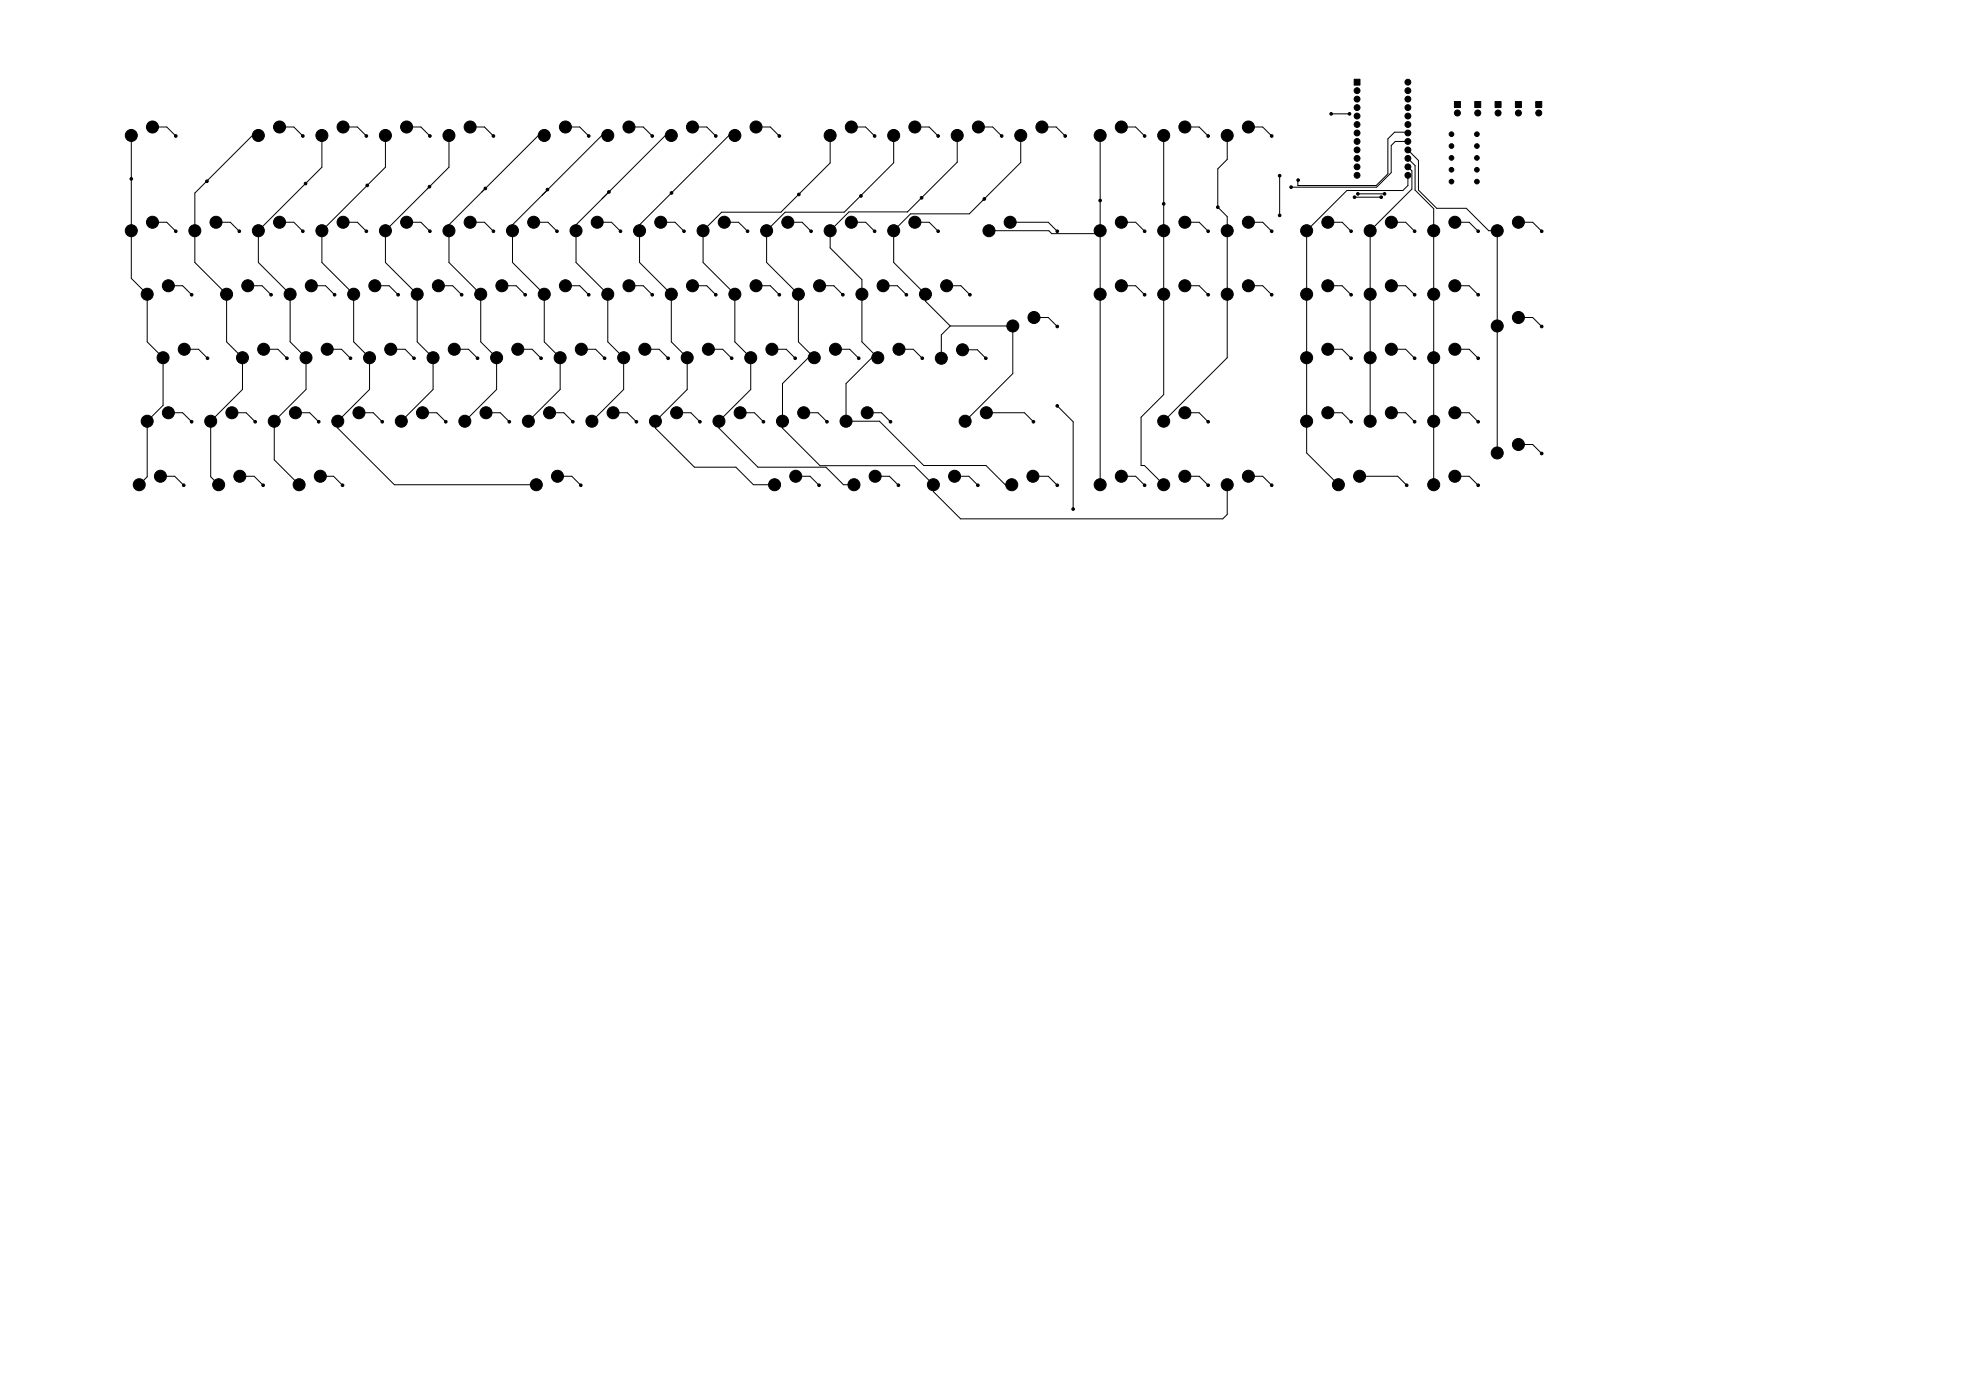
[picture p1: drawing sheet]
<svg xmlns="http://www.w3.org/2000/svg" width="594mm" height="420mm" viewBox="0 0 594 420" stroke-linecap="round" stroke-linejoin="round" font-family="sans-serif">
<g fill="#000" stroke="#000" stroke-width=".3">
<path d="M406 23.8h1.8v1.7h-1.8zM436.1 30.5h1.8v1.8h-1.8zM442.2 30.5h1.8v1.8h-1.8zM448.3 30.5h1.8v1.8h-1.8zM454.4 30.5h1.8v1.8h-1.8zM460.5 30.5h1.8v1.8h-1.8z"/>
<circle cx="45.7" cy="38.1" r="1.8"/>
<circle cx="83.8" cy="38.1" r="1.8"/>
<circle cx="102.9" cy="38.1" r="1.8"/>
<circle cx="121.9" cy="38.1" r="1.8"/>
<circle cx="141" cy="38.1" r="1.8"/>
<circle cx="169.5" cy="38.1" r="1.8"/>
<circle cx="188.6" cy="38.1" r="1.8"/>
<circle cx="207.6" cy="38.1" r="1.8"/>
<circle cx="226.7" cy="38.1" r="1.8"/>
<circle cx="255.3" cy="38.1" r="1.8"/>
<circle cx="274.3" cy="38.1" r="1.8"/>
<circle cx="293.4" cy="38.1" r="1.8"/>
<circle cx="312.4" cy="38.1" r="1.8"/>
<circle cx="336.2" cy="38.1" r="1.8"/>
<circle cx="355.3" cy="38.1" r="1.8"/>
<circle cx="374.3" cy="38.1" r="1.8"/>
<circle cx="399.2" cy="34.2" r=".4"/>
<circle cx="404.7" cy="34.2" r=".4"/>
<circle cx="406.9" cy="39.9" r=".88"/>
<circle cx="406.9" cy="34.8" r=".88"/>
<circle cx="406.9" cy="27.2" r=".88"/>
<circle cx="406.9" cy="29.7" r=".88"/>
<circle cx="406.9" cy="32.3" r=".88"/>
<circle cx="406.9" cy="37.4" r=".88"/>
<circle cx="422.2" cy="32.3" r=".88"/>
<circle cx="422.2" cy="27.2" r=".88"/>
<circle cx="422.2" cy="39.9" r=".88"/>
<circle cx="422.2" cy="37.4" r=".88"/>
<circle cx="422.2" cy="24.7" r=".88"/>
<circle cx="422.2" cy="34.8" r=".88"/>
<circle cx="422.2" cy="29.7" r=".88"/>
<circle cx="437" cy="33.9" r=".9"/>
<circle cx="443.1" cy="33.9" r=".9"/>
<circle cx="449.2" cy="33.9" r=".9"/>
<circle cx="455.3" cy="33.9" r=".9"/>
<circle cx="461.4" cy="33.9" r=".9"/>
<circle cx="39.4" cy="53.7" r=".4"/>
<circle cx="39.4" cy="40.6" r="1.8"/>
<circle cx="52.7" cy="40.8" r=".4"/>
<circle cx="62.1" cy="54.4" r=".4"/>
<circle cx="77.5" cy="40.6" r="1.8"/>
<circle cx="90.8" cy="40.8" r=".4"/>
<circle cx="91.6" cy="55.1" r=".4"/>
<circle cx="96.5" cy="40.6" r="1.8"/>
<circle cx="109.9" cy="40.8" r=".4"/>
<circle cx="110.1" cy="55.6" r=".4"/>
<circle cx="115.6" cy="40.6" r="1.8"/>
<circle cx="128.8" cy="56" r=".4"/>
<circle cx="128.9" cy="40.8" r=".4"/>
<circle cx="134.6" cy="40.6" r="1.8"/>
<circle cx="145.5" cy="56.5" r=".4"/>
<circle cx="148" cy="40.8" r=".4"/>
<circle cx="163.2" cy="40.6" r="1.8"/>
<circle cx="164.2" cy="56.9" r=".4"/>
<circle cx="176.5" cy="40.8" r=".4"/>
<circle cx="182.2" cy="40.6" r="1.8"/>
<circle cx="182.6" cy="57.6" r=".4"/>
<circle cx="195.6" cy="40.8" r=".4"/>
<circle cx="201.3" cy="40.6" r="1.8"/>
<circle cx="201.4" cy="57.9" r=".4"/>
<circle cx="214.6" cy="40.8" r=".4"/>
<circle cx="220.3" cy="40.6" r="1.8"/>
<circle cx="233.7" cy="40.8" r=".4"/>
<circle cx="239.5" cy="58.3" r=".4"/>
<circle cx="248.9" cy="40.6" r="1.8"/>
<circle cx="258.2" cy="58.8" r=".4"/>
<circle cx="262.3" cy="40.8" r=".4"/>
<circle cx="268" cy="40.6" r="1.8"/>
<circle cx="276.3" cy="59.3" r=".4"/>
<circle cx="281.3" cy="40.8" r=".4"/>
<circle cx="287" cy="40.6" r="1.8"/>
<circle cx="295.2" cy="59.7" r=".4"/>
<circle cx="300.4" cy="40.8" r=".4"/>
<circle cx="306.1" cy="40.6" r="1.8"/>
<circle cx="319.4" cy="40.8" r=".4"/>
<circle cx="329.9" cy="40.6" r="1.8"/>
<circle cx="343.2" cy="40.8" r=".4"/>
<circle cx="348.9" cy="40.6" r="1.8"/>
<circle cx="362.3" cy="40.8" r=".4"/>
<circle cx="368" cy="40.6" r="1.8"/>
<circle cx="381.3" cy="40.8" r=".4"/>
<circle cx="383.7" cy="52.7" r=".4"/>
<circle cx="387.1" cy="56.1" r=".4"/>
<circle cx="389.2" cy="54" r=".4"/>
<circle cx="406.2" cy="59.2" r=".4"/>
<circle cx="406.9" cy="45" r=".88"/>
<circle cx="406.9" cy="50.1" r=".88"/>
<circle cx="406.9" cy="47.5" r=".88"/>
<circle cx="406.9" cy="52.6" r=".88"/>
<circle cx="406.9" cy="42.4" r=".88"/>
<circle cx="407.2" cy="58.2" r=".4"/>
<circle cx="414.2" cy="59.2" r=".4"/>
<circle cx="415.2" cy="58.2" r=".4"/>
<circle cx="422.2" cy="42.4" r=".88"/>
<circle cx="422.2" cy="52.6" r=".88"/>
<circle cx="422.2" cy="47.5" r=".88"/>
<circle cx="422.2" cy="50.1" r=".88"/>
<circle cx="422.2" cy="45" r=".88"/>
<circle cx="435.2" cy="43.8" r=".7"/>
<circle cx="435.2" cy="54.5" r=".7"/>
<circle cx="435.2" cy="40.3" r=".7"/>
<circle cx="435.2" cy="50.9" r=".7"/>
<circle cx="435.2" cy="47.4" r=".7"/>
<circle cx="442.8" cy="50.9" r=".7"/>
<circle cx="442.8" cy="54.5" r=".7"/>
<circle cx="442.8" cy="40.3" r=".7"/>
<circle cx="442.8" cy="47.4" r=".7"/>
<circle cx="442.8" cy="43.8" r=".7"/>
<circle cx="39.4" cy="69.2" r="1.8"/>
<circle cx="45.7" cy="66.7" r="1.8"/>
<circle cx="52.7" cy="69.4" r=".4"/>
<circle cx="58.4" cy="69.2" r="1.8"/>
<circle cx="64.8" cy="66.7" r="1.8"/>
<circle cx="71.8" cy="69.4" r=".4"/>
<circle cx="77.5" cy="69.2" r="1.8"/>
<circle cx="83.8" cy="66.7" r="1.8"/>
<circle cx="90.8" cy="69.4" r=".4"/>
<circle cx="96.5" cy="69.2" r="1.8"/>
<circle cx="102.9" cy="66.7" r="1.8"/>
<circle cx="109.9" cy="69.4" r=".4"/>
<circle cx="115.6" cy="69.2" r="1.8"/>
<circle cx="121.9" cy="66.7" r="1.8"/>
<circle cx="128.9" cy="69.4" r=".4"/>
<circle cx="134.6" cy="69.2" r="1.8"/>
<circle cx="141" cy="66.7" r="1.8"/>
<circle cx="148" cy="69.4" r=".4"/>
<circle cx="153.7" cy="69.2" r="1.8"/>
<circle cx="160" cy="66.7" r="1.8"/>
<circle cx="167" cy="69.4" r=".4"/>
<circle cx="172.7" cy="69.2" r="1.8"/>
<circle cx="179.1" cy="66.7" r="1.8"/>
<circle cx="186.1" cy="69.4" r=".4"/>
<circle cx="191.8" cy="69.2" r="1.8"/>
<circle cx="198.1" cy="66.7" r="1.8"/>
<circle cx="205.1" cy="69.4" r=".4"/>
<circle cx="210.8" cy="69.2" r="1.8"/>
<circle cx="217.2" cy="66.7" r="1.8"/>
<circle cx="224.2" cy="69.4" r=".4"/>
<circle cx="229.9" cy="69.2" r="1.8"/>
<circle cx="236.2" cy="66.7" r="1.8"/>
<circle cx="243.2" cy="69.4" r=".4"/>
<circle cx="248.9" cy="69.2" r="1.8"/>
<circle cx="255.3" cy="66.7" r="1.8"/>
<circle cx="262.3" cy="69.4" r=".4"/>
<circle cx="268" cy="69.2" r="1.8"/>
<circle cx="274.3" cy="66.7" r="1.8"/>
<circle cx="281.3" cy="69.4" r=".4"/>
<circle cx="296.5" cy="69.2" r="1.8"/>
<circle cx="302.9" cy="66.7" r="1.8"/>
<circle cx="317" cy="69.4" r=".4"/>
<circle cx="329.9" cy="69.2" r="1.8"/>
<circle cx="329.9" cy="60.2" r=".4"/>
<circle cx="336.2" cy="66.7" r="1.8"/>
<circle cx="343.2" cy="69.4" r=".4"/>
<circle cx="348.9" cy="69.2" r="1.8"/>
<circle cx="348.9" cy="61.2" r=".4"/>
<circle cx="355.3" cy="66.7" r="1.8"/>
<circle cx="362.3" cy="69.4" r=".4"/>
<circle cx="365.2" cy="62.2" r=".4"/>
<circle cx="368" cy="69.2" r="1.8"/>
<circle cx="374.3" cy="66.7" r="1.8"/>
<circle cx="381.3" cy="69.4" r=".4"/>
<circle cx="383.7" cy="64.6" r=".4"/>
<circle cx="391.8" cy="69.2" r="1.8"/>
<circle cx="398.1" cy="66.7" r="1.8"/>
<circle cx="405.1" cy="69.4" r=".4"/>
<circle cx="410.8" cy="69.2" r="1.8"/>
<circle cx="417.2" cy="66.7" r="1.8"/>
<circle cx="424.2" cy="69.4" r=".4"/>
<circle cx="429.9" cy="69.2" r="1.8"/>
<circle cx="436.2" cy="66.7" r="1.8"/>
<circle cx="443.2" cy="69.4" r=".4"/>
<circle cx="448.9" cy="69.2" r="1.8"/>
<circle cx="455.3" cy="66.7" r="1.8"/>
<circle cx="462.3" cy="69.4" r=".4"/>
<circle cx="44.1" cy="88.3" r="1.8"/>
<circle cx="50.5" cy="85.7" r="1.8"/>
<circle cx="57.5" cy="88.4" r=".4"/>
<circle cx="67.9" cy="88.3" r="1.8"/>
<circle cx="74.3" cy="85.7" r="1.8"/>
<circle cx="81.3" cy="88.4" r=".4"/>
<circle cx="87" cy="88.3" r="1.8"/>
<circle cx="93.3" cy="85.7" r="1.8"/>
<circle cx="100.3" cy="88.4" r=".4"/>
<circle cx="106" cy="88.3" r="1.8"/>
<circle cx="112.4" cy="85.7" r="1.8"/>
<circle cx="119.4" cy="88.4" r=".4"/>
<circle cx="125.1" cy="88.3" r="1.8"/>
<circle cx="131.4" cy="85.7" r="1.8"/>
<circle cx="138.4" cy="88.4" r=".4"/>
<circle cx="144.1" cy="88.3" r="1.8"/>
<circle cx="150.5" cy="85.7" r="1.8"/>
<circle cx="157.5" cy="88.4" r=".4"/>
<circle cx="163.2" cy="88.3" r="1.8"/>
<circle cx="169.5" cy="85.7" r="1.8"/>
<circle cx="176.5" cy="88.4" r=".4"/>
<circle cx="182.2" cy="88.3" r="1.8"/>
<circle cx="188.6" cy="85.7" r="1.8"/>
<circle cx="195.6" cy="88.4" r=".4"/>
<circle cx="201.3" cy="88.3" r="1.8"/>
<circle cx="207.6" cy="85.7" r="1.8"/>
<circle cx="214.6" cy="88.4" r=".4"/>
<circle cx="220.3" cy="88.3" r="1.8"/>
<circle cx="226.7" cy="85.7" r="1.8"/>
<circle cx="233.7" cy="88.4" r=".4"/>
<circle cx="239.4" cy="88.3" r="1.8"/>
<circle cx="245.7" cy="85.7" r="1.8"/>
<circle cx="252.7" cy="88.4" r=".4"/>
<circle cx="258.4" cy="88.3" r="1.8"/>
<circle cx="264.8" cy="85.7" r="1.8"/>
<circle cx="271.8" cy="88.4" r=".4"/>
<circle cx="277.5" cy="88.3" r="1.8"/>
<circle cx="283.8" cy="85.7" r="1.8"/>
<circle cx="290.8" cy="88.4" r=".4"/>
<circle cx="303.7" cy="97.8" r="1.8"/>
<circle cx="310" cy="95.3" r="1.8"/>
<circle cx="317" cy="97.9" r=".4"/>
<circle cx="329.9" cy="88.3" r="1.8"/>
<circle cx="336.2" cy="85.7" r="1.8"/>
<circle cx="343.2" cy="88.4" r=".4"/>
<circle cx="348.9" cy="88.3" r="1.8"/>
<circle cx="355.3" cy="85.7" r="1.8"/>
<circle cx="362.3" cy="88.4" r=".4"/>
<circle cx="368" cy="88.3" r="1.8"/>
<circle cx="374.3" cy="85.7" r="1.8"/>
<circle cx="381.3" cy="88.4" r=".4"/>
<circle cx="391.8" cy="88.3" r="1.8"/>
<circle cx="398.1" cy="85.7" r="1.8"/>
<circle cx="405.1" cy="88.4" r=".4"/>
<circle cx="410.8" cy="88.3" r="1.8"/>
<circle cx="417.2" cy="85.7" r="1.8"/>
<circle cx="424.2" cy="88.4" r=".4"/>
<circle cx="429.9" cy="88.3" r="1.8"/>
<circle cx="436.2" cy="85.7" r="1.8"/>
<circle cx="443.2" cy="88.4" r=".4"/>
<circle cx="448.9" cy="97.8" r="1.8"/>
<circle cx="455.3" cy="95.3" r="1.8"/>
<circle cx="462.3" cy="97.9" r=".4"/>
<circle cx="48.9" cy="107.3" r="1.8"/>
<circle cx="55.2" cy="104.8" r="1.8"/>
<circle cx="62.2" cy="107.5" r=".4"/>
<circle cx="72.7" cy="107.3" r="1.8"/>
<circle cx="79.1" cy="104.8" r="1.8"/>
<circle cx="86" cy="107.5" r=".4"/>
<circle cx="91.8" cy="107.3" r="1.8"/>
<circle cx="98.1" cy="104.8" r="1.8"/>
<circle cx="105.1" cy="107.5" r=".4"/>
<circle cx="110.8" cy="107.3" r="1.8"/>
<circle cx="117.2" cy="104.8" r="1.8"/>
<circle cx="124.1" cy="107.5" r=".4"/>
<circle cx="129.9" cy="107.3" r="1.8"/>
<circle cx="136.2" cy="104.8" r="1.8"/>
<circle cx="143.2" cy="107.5" r=".4"/>
<circle cx="148.9" cy="107.3" r="1.8"/>
<circle cx="155.3" cy="104.8" r="1.8"/>
<circle cx="162.2" cy="107.5" r=".4"/>
<circle cx="168" cy="107.3" r="1.8"/>
<circle cx="174.3" cy="104.8" r="1.8"/>
<circle cx="181.3" cy="107.5" r=".4"/>
<circle cx="187" cy="107.3" r="1.8"/>
<circle cx="193.4" cy="104.8" r="1.8"/>
<circle cx="200.3" cy="107.5" r=".4"/>
<circle cx="206.1" cy="107.3" r="1.8"/>
<circle cx="212.4" cy="104.8" r="1.8"/>
<circle cx="219.4" cy="107.5" r=".4"/>
<circle cx="225.1" cy="107.3" r="1.8"/>
<circle cx="231.5" cy="104.8" r="1.8"/>
<circle cx="238.4" cy="107.5" r=".4"/>
<circle cx="244.2" cy="107.3" r="1.8"/>
<circle cx="250.5" cy="104.8" r="1.8"/>
<circle cx="257.5" cy="107.5" r=".4"/>
<circle cx="263.2" cy="107.3" r="1.8"/>
<circle cx="269.6" cy="104.8" r="1.8"/>
<circle cx="276.5" cy="107.5" r=".4"/>
<circle cx="282.3" cy="107.5" r="1.8"/>
<circle cx="288.6" cy="104.9" r="1.8"/>
<circle cx="295.6" cy="107.5" r=".4"/>
<circle cx="391.8" cy="107.3" r="1.8"/>
<circle cx="398.1" cy="104.8" r="1.8"/>
<circle cx="405.1" cy="107.5" r=".4"/>
<circle cx="410.8" cy="107.3" r="1.8"/>
<circle cx="417.2" cy="104.8" r="1.8"/>
<circle cx="424.2" cy="107.5" r=".4"/>
<circle cx="429.9" cy="107.3" r="1.8"/>
<circle cx="436.2" cy="104.8" r="1.8"/>
<circle cx="443.2" cy="107.5" r=".4"/>
<circle cx="44.1" cy="126.4" r="1.8"/>
<circle cx="50.5" cy="123.8" r="1.8"/>
<circle cx="57.5" cy="126.5" r=".4"/>
<circle cx="63.2" cy="126.4" r="1.8"/>
<circle cx="69.5" cy="123.8" r="1.8"/>
<circle cx="76.5" cy="126.5" r=".4"/>
<circle cx="82.2" cy="126.4" r="1.8"/>
<circle cx="88.6" cy="123.8" r="1.8"/>
<circle cx="95.6" cy="126.5" r=".4"/>
<circle cx="101.3" cy="126.4" r="1.8"/>
<circle cx="107.6" cy="123.8" r="1.8"/>
<circle cx="114.6" cy="126.5" r=".4"/>
<circle cx="120.3" cy="126.4" r="1.8"/>
<circle cx="126.7" cy="123.8" r="1.8"/>
<circle cx="133.7" cy="126.5" r=".4"/>
<circle cx="139.4" cy="126.4" r="1.8"/>
<circle cx="145.7" cy="123.8" r="1.8"/>
<circle cx="152.7" cy="126.5" r=".4"/>
<circle cx="158.4" cy="126.4" r="1.8"/>
<circle cx="164.8" cy="123.8" r="1.8"/>
<circle cx="171.8" cy="126.5" r=".4"/>
<circle cx="177.5" cy="126.4" r="1.8"/>
<circle cx="183.8" cy="123.8" r="1.8"/>
<circle cx="190.8" cy="126.5" r=".4"/>
<circle cx="196.5" cy="126.4" r="1.8"/>
<circle cx="202.9" cy="123.8" r="1.8"/>
<circle cx="209.9" cy="126.5" r=".4"/>
<circle cx="215.6" cy="126.4" r="1.8"/>
<circle cx="221.9" cy="123.8" r="1.8"/>
<circle cx="228.9" cy="126.5" r=".4"/>
<circle cx="234.6" cy="126.4" r="1.8"/>
<circle cx="241" cy="123.8" r="1.8"/>
<circle cx="248" cy="126.5" r=".4"/>
<circle cx="253.7" cy="126.4" r="1.8"/>
<circle cx="260" cy="123.8" r="1.8"/>
<circle cx="267" cy="126.5" r=".4"/>
<circle cx="289.4" cy="126.4" r="1.8"/>
<circle cx="295.8" cy="123.8" r="1.8"/>
<circle cx="309.9" cy="126.5" r=".4"/>
<circle cx="317" cy="121.8" r=".4"/>
<circle cx="348.9" cy="126.4" r="1.8"/>
<circle cx="355.3" cy="123.8" r="1.8"/>
<circle cx="362.3" cy="126.5" r=".4"/>
<circle cx="391.8" cy="126.4" r="1.8"/>
<circle cx="398.1" cy="123.8" r="1.8"/>
<circle cx="405.1" cy="126.5" r=".4"/>
<circle cx="410.8" cy="126.4" r="1.8"/>
<circle cx="417.2" cy="123.8" r="1.8"/>
<circle cx="424.2" cy="126.5" r=".4"/>
<circle cx="429.9" cy="126.4" r="1.8"/>
<circle cx="436.2" cy="123.8" r="1.8"/>
<circle cx="443.2" cy="126.5" r=".4"/>
<circle cx="448.9" cy="135.9" r="1.8"/>
<circle cx="455.3" cy="133.4" r="1.8"/>
<circle cx="462.3" cy="136" r=".4"/>
<circle cx="41.8" cy="145.4" r="1.8"/>
<circle cx="48.1" cy="142.9" r="1.8"/>
<circle cx="55.1" cy="145.6" r=".4"/>
<circle cx="65.6" cy="145.4" r="1.8"/>
<circle cx="71.9" cy="142.9" r="1.8"/>
<circle cx="78.9" cy="145.6" r=".4"/>
<circle cx="89.7" cy="145.4" r="1.8"/>
<circle cx="96" cy="142.9" r="1.8"/>
<circle cx="102.7" cy="145.6" r=".4"/>
<circle cx="160.8" cy="145.4" r="1.8"/>
<circle cx="167.2" cy="142.9" r="1.8"/>
<circle cx="174.1" cy="145.6" r=".4"/>
<circle cx="232.3" cy="145.4" r="1.8"/>
<circle cx="238.6" cy="142.9" r="1.8"/>
<circle cx="245.6" cy="145.6" r=".4"/>
<circle cx="256.1" cy="145.4" r="1.8"/>
<circle cx="262.4" cy="142.9" r="1.8"/>
<circle cx="269.4" cy="145.6" r=".4"/>
<circle cx="279.9" cy="145.4" r="1.8"/>
<circle cx="286.2" cy="142.9" r="1.8"/>
<circle cx="293.2" cy="145.6" r=".4"/>
<circle cx="303.4" cy="145.4" r="1.8"/>
<circle cx="309.7" cy="142.9" r="1.8"/>
<circle cx="317" cy="145.6" r=".4"/>
<circle cx="321.8" cy="152.7" r=".4"/>
<circle cx="329.9" cy="145.4" r="1.8"/>
<circle cx="336.2" cy="142.9" r="1.8"/>
<circle cx="343.2" cy="145.6" r=".4"/>
<circle cx="348.9" cy="145.4" r="1.8"/>
<circle cx="355.3" cy="142.9" r="1.8"/>
<circle cx="362.3" cy="145.6" r=".4"/>
<circle cx="368" cy="145.4" r="1.8"/>
<circle cx="374.3" cy="142.9" r="1.8"/>
<circle cx="381.3" cy="145.6" r=".4"/>
<circle cx="401.3" cy="145.4" r="1.8"/>
<circle cx="407.7" cy="142.9" r="1.8"/>
<circle cx="421.8" cy="145.6" r=".4"/>
<circle cx="429.9" cy="145.4" r="1.8"/>
<circle cx="436.2" cy="142.9" r="1.8"/>
<circle cx="443.2" cy="145.6" r=".4"/>
</g>
<g fill="none" stroke="#000" stroke-width=".3">
<path d="M45.7 38.1h4.3l2.7 2.7M83.8 38.1h4.3l2.7 2.7M102.9 38.1h4.3l2.7 2.7M121.9 38.1h4.3l2.7 2.7M141 38.1h4.3l2.7 2.7M169.5 38.1h4.3l2.7 2.7M188.6 38.1h4.3l2.7 2.7M207.6 38.1h4.3l2.7 2.7M226.7 38.1h4.3l2.7 2.7M255.3 38.1h4.3l2.7 2.7M274.3 38.1h4.3l2.7 2.7M293.4 38.1h4.3l2.7 2.7"/>
<path d="M312.4 38.1h4.3l2.7 2.7M336.2 38.1h4.3l2.7 2.7M355.3 38.1h4.3l2.7 2.7M374.3 38.1h4.3l2.7 2.7M399.2 34.2h5.5M422.2 39.9l-.3-.2h-3.7l-2 2v10.5l-3.5 3.5h-23.5v-1.7M39.4 40.6v42.9l4.7 4.8v14.3l4.8 4.7v14.3l-4.8 4.8v16.6l-2.3 2.4M62 54.4h.1M77.5 40.6h-1.8l-17.3 17.3v20.8l9.5 9.6v14.3l4.8 4.7v9.5l-9.5 9.6v16.6l2.4 2.4M96.5 40.6v9.6l-19 19v9.5l9.5 9.6v14.3l4.8 4.7v9.5l-9.6 9.6v11.6l7.5 7.4M115.6 40.6v9.6l-19.1 19v9.5l9.5 9.6v14.3l4.8 4.7v9.5l-9.5 9.6v2.1l16.9 16.9h42.6M134.6 40.6v9.6l-19 19v9.5l9.5 9.6v14.3l4.8 4.7v9.5l-9.6 9.6"/>
<path d="M163.2 40.6h-1.8l-26.8 26.8v11.3l9.5 9.6v14.3l4.8 4.7v9.5l-9.5 9.6M164.2 56.9v.1M182.2 40.6h-1.7l-26.8 26.8v11.3l9.5 9.6v14.3l4.8 4.7v9.5l-9.6 9.6M201.3 40.6h-1.8l-26.8 26.8v11.3l9.5 9.6v14.3l4.8 4.7v9.5l-9.5 9.6M201.3 57.9h.1M220.3 40.6h-1.7l-26.8 26.8v11.3l9.5 9.6v14.3l4.8 4.7v9.5l-9.6 9.6v2.1l11.7 11.7h12.5l5.2 5.2h6.4M239.5 58.3h.1M248.9 40.6v8.3l-14.7 14.8h-17.8l-5.6 5.5v9.5l9.5 9.6v14.3l4.8 4.7v9.5l-9.5 9.6v2.1l11.7 11.7h20.4l5.2 5.2h3.2M258.2 58.7v.1M268 40.6v8.2l-14.8 14.9h-17.8l-5.5 5.5v9.5l9.5 9.6v14.3l4.8 4.7h-1.8l-7.8 7.8v13.4l11.3 11.2h28.3l5.7 5.7v2.1l8.1 8.2h78.7l1.3-1.4v-8.9M287 40.6v8.1l-14.8 14.9h-17.6l-5.7 5.6v5.2l9.5 9.5v18.7l4.8 4.7h-1.8l-7.7 7.8v11.3h10l13.3 13.3h18.7l5.7 5.7h2M295.2 59.7l-.5 .5"/>
<path d="M306.1 40.6v8.1l-15.4 15.5h-17.7l-5 5v9.5l9.5 9.6v2.1l7.4 7.4M329.9 40.6v104.8M348.9 40.6v77.8l-6.7 6.8v14.5h1l5.7 5.7M368 40.6v7.2l-2.8 2.9v11.5l2.8 2.8v42.3l-19.1 19.1M383.7 52.7v11.9M406.2 59.2h8M407.2 58.2h8M422.2 42.4h-3.8l-1.2 1.3v8.1l-4.4 4.4-25.7-.1M422.2 45l3.1 3.1v8.9l5.5 5.5h8.9l6.7 6.7h2.5M422.2 52.6v3.1l-1.5 1.5h-16.8l-12.1 12v66.7l9.5 9.5M422.2 47.5l2.1 2.2v7.3l5.6 5.6v82.8M422.2 50.1l1.2 1.2v5.4l-12.6 12.5v57.2"/>
<path d="M45.7 66.7h4.3l2.7 2.7M64.8 66.7h4.3l2.7 2.7M83.8 66.7h4.3l2.7 2.7M102.9 66.7h4.3l2.7 2.7M121.9 66.7h4.3l2.7 2.7M141 66.7h4.3l2.7 2.7M160 66.7h4.3l2.7 2.7M179.1 66.7h4.3l2.7 2.7M198.1 66.7h4.3l2.7 2.7M217.2 66.7h4.3l2.7 2.7M236.2 66.7h4.3l2.7 2.7M255.3 66.7h4.3l2.7 2.7"/>
<path d="M274.3 66.7h4.3l2.7 2.7M294.7 60.2h.1M296.5 69.2h18l.9 .9h13.6l.9-.9M302.9 66.7h11.4l2.7 2.7M336.2 66.7h4.3l2.7 2.7M355.3 66.7h4.3l2.7 2.7M374.3 66.7h4.3l2.7 2.7M398.1 66.7h4.3l2.7 2.7M417.2 66.7h4.3l2.7 2.7M436.2 66.7h4.3l2.7 2.7M448.9 69.2l-.8 .9M448.9 69.2v66.7"/>
<path d="M455.3 66.7h4.3l2.7 2.7M50.5 85.7h4.3l2.7 2.7M74.3 85.7h4.3l2.7 2.7M93.3 85.7h4.3l2.7 2.7M112.4 85.7h4.3l2.7 2.7M131.4 85.7h4.3l2.7 2.7M150.5 85.7h4.3l2.7 2.7M169.5 85.7h4.3l2.7 2.7M188.6 85.7h4.3l2.7 2.7M207.6 85.7h4.3l2.7 2.7M226.7 85.7h4.3l2.7 2.7M245.7 85.7h4.3l2.7 2.7"/>
<path d="M264.8 85.7h4.3l2.7 2.7M283.8 85.7h4.3l2.7 2.7M284.9 97.8h18.8v14.3l-14.3 14.3M284.9 97.8l-2.6 2.7v7M310 95.3h4.3l2.7 2.6M336.2 85.7h4.3l2.7 2.7M355.3 85.7h4.3l2.7 2.7M374.3 85.7h4.3l2.7 2.7M398.1 85.7h4.3l2.7 2.7M417.2 85.7h4.3l2.7 2.7M436.2 85.7h4.3l2.7 2.7M455.3 95.3h4.3l2.7 2.6"/>
<path d="M55.2 104.8h4.3l2.7 2.7M79.1 104.8h4.2l2.7 2.7M98.1 104.8h4.3l2.7 2.7M117.2 104.8h4.2l2.7 2.7M136.2 104.8h4.3l2.7 2.7M155.3 104.8h4.2l2.7 2.7M174.3 104.8h4.3l2.7 2.7M193.4 104.8h4.2l2.7 2.7M212.4 104.8h4.3l2.7 2.7M231.5 104.8h4.2l2.7 2.7M250.5 104.8h4.3l2.7 2.7M269.6 104.8h4.2l2.7 2.7"/>
<path d="M288.6 104.9h4.5l2.5 2.6M398.1 104.8h4.3l2.7 2.7M417.2 104.8h4.3l2.7 2.7M436.2 104.8h4.3l2.7 2.7M50.5 123.8h4.3l2.7 2.7M69.5 123.8h4.3l2.7 2.7M88.6 123.8h4.3l2.7 2.7M107.6 123.8h4.3l2.7 2.7M126.7 123.8h4.3l2.7 2.7M145.7 123.8h4.3l2.7 2.7M164.8 123.8h4.3l2.7 2.7M183.8 123.8h4.3l2.7 2.7"/>
<path d="M202.9 123.8h4.3l2.7 2.7M221.9 123.8h4.3l2.7 2.7M241 123.8h4.3l2.7 2.7M260 123.8h4.3l2.7 2.7M295.8 123.8h11.4l2.7 2.7M317 121.8l4.8 4.7v26.2M355.3 123.8h4.3l2.7 2.7M398.1 123.8h4.3l2.7 2.7M417.2 123.8h4.3l2.7 2.7M436.2 123.8h4.3l2.7 2.7M455.3 133.4h4.3l2.7 2.6M48.1 142.9h4.3l2.7 2.7"/>
<path d="M71.9 142.9h4.3l2.7 2.7M96 142.9h4l2.7 2.7M167.2 142.9h4.2l2.7 2.7M238.6 142.9h4.3l2.7 2.7M262.4 142.9h4.3l2.7 2.7M286.2 142.9h4.3l2.7 2.7M309.7 142.9h4.6l2.7 2.7M336.2 142.9h4.3l2.7 2.7M355.3 142.9h4.3l2.7 2.7M374.3 142.9h4.3l2.7 2.7M407.7 142.9h11.4l2.7 2.7M436.2 142.9h4.3l2.7 2.7"/>
</g>
</svg>
